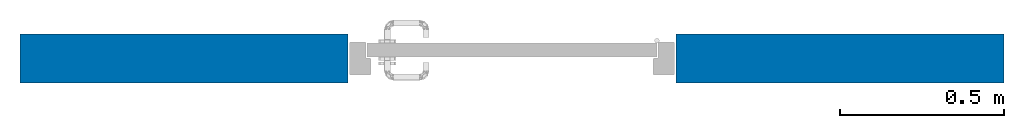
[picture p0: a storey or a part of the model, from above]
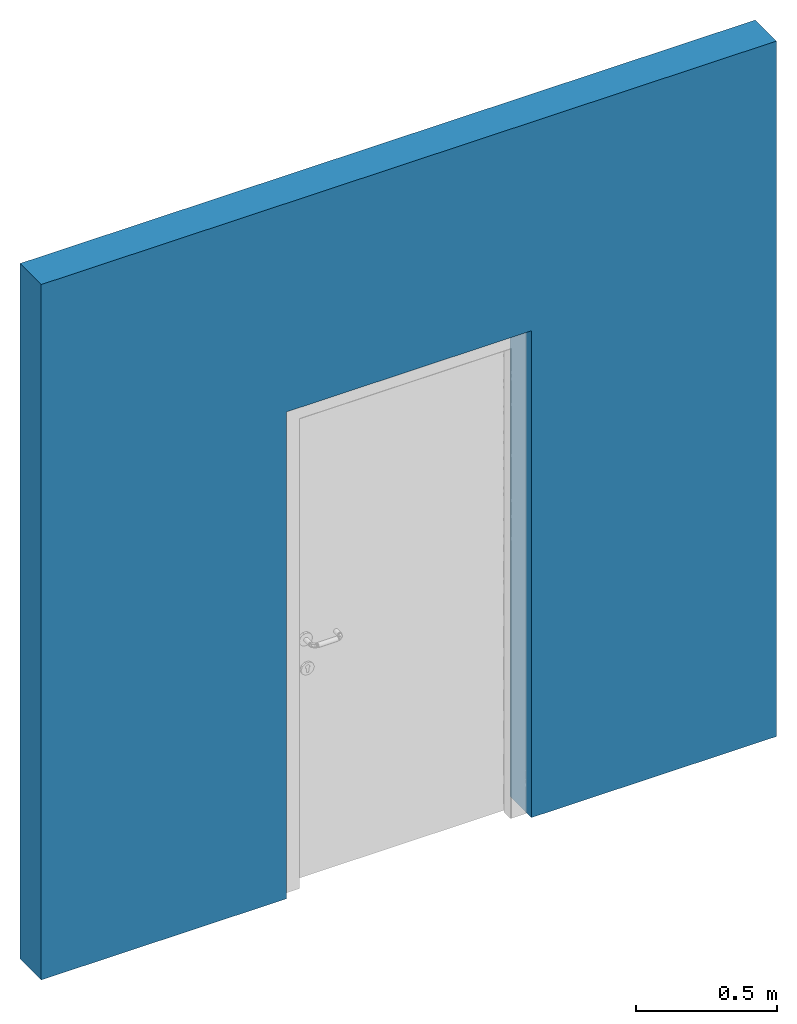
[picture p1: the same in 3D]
Properties of the parts of a building model (IFC2X3)

# File
Description: ViewDefinition [CoordinationView_V2.0]
Time: 2015-03-31T15:16:15
Written by: The EXPRESS Data Manager Version 5.01.0100.02.64mod : 6 Jun 2012
Made in: 20130709_2115(x64) - Exporter 3.12.0.0 - Alternate UI 2.12.0.0
Comment: STEP Physical File produced by: The EXPRESS Data Manager Version 5.01.0100.02.64mod : 6 Jun 2012 * Module: EDMstepFileFactory/EDMstandAlone * Creation date: Tue Mar 31 15:16:15 2015 * Host: NCL-TA29 * Database: C:\Users\Vickersc\AppData\Local\Temp\{95549542-646E-4CD0-B614-C0AC66229B2C}\ifc * Database version: 5507 * Database creation date: Tue Mar 31 15:16:13 2015 * Schema: IFC2X3 * Model: DataRepository.ifc * Model creation date: Tue Mar 31 15:16:14 2015 * Header model: DataRepository.ifc_HeaderModel * Header model creation date: Tue Mar 31 15:16:14 2015 * EDMuser: sdai-user * EDMgroup: sdai-group * License ID and type: 5605 : Permanent license. Expiry date: * EDMstepFileFactory options: 020000

# IfcProject
LongName: X:\NBL\Manufacturer\A\Assa Abloy 0060A_8204\WIP\Xbim\Batch3\IFC\NBS_AssaAbloyLtd_DrsetSym_AASDMetalThermoInsulatingUValueDoor_Single.ifc

# IfcSite, Default
RefLatitude: 42, 24, 53, 508911; RefLongitude: -71, -15, -29, -58837; RefElevation: 0 mm

# IfcBuildingStorey, Level 1
LongName: Level 1; Elevation: 0 mm

# IfcDoor: 1000x2100mm, NBS_AssaAbloyLtd_DrsetSym_AASDMetalThermoInsulatingUValueDoor_Single:1000x2100mm:1524841
In: Level 1
Type - ParameterTakesPrecedence: no; Sizeable: no; Material: NBS_Concept
Type - Pset_DoorCommon - AcousticRating: Unrated; FireExit: no; FireRating: Unrated; GlazingAreaFraction: 0; HandicapAccessible: yes; HasDrive: no; Infiltration: 0 m3/s; IsExternal: no; Reference: n/a; SecurityRating: Unrated; SelfClosing: yes; SmokeStop: no; ThermalTransmittance: 0 kg/K/s3
Type - COBie - AccessibilityPerformance: n/a; CodePerformance: n/a; Constituents: n/a; Features: n/a; Finish: n/a; Grade: n/a; Manufacturer: sales@assaabloy.co.uk; Material: n/a; ModelReference: AASD ThermoInsulating UValue Door; NominalHeight: 2100 mm; NominalLength: 0 mm; NominalWidth: 1000 mm; ReplacementCost: n/a; Shape: Rectangle; Size: 1000 x 2100 mm; SustainabilityPerformance: n/a; WarrantyDescription: n/a; WarrantyDurationParts: n/a; WarrantyGuarantorParts: n/a; AssetType: Fixed; Category: n/a; DurationUnit: year; Name: DoorsetSystem_AASDMetalThermoInsulatingUValueDoor_Single-1000x2100mm_AssaAbloyLtd; WarrantyDurationUnit: year; ExpectedLife: n/a; Description: Single metal thermo insulating U-value door; Color: n/a; ModelNumber: n/a; WarrantyDurationLabor: n/a; WarrantyGuarantorLabor: n/a
Type - NBS_General - Revision: n/a; NBSOfficeMasterTag: n/a; Author: NBS; BIMObjectName: NBS_AssaAbloyLtd_DoorsetSystem_AASDMetalThermoInsulatingUValueDoor_Single-1000x2100mm; ManufacturerName: Assa Abloy Ltd; ManufacturerURL: www.assaabloy.co.uk; NBSCertification: www.nationalbimlibrary.com/assa-abloy/single-metal-thermo-insulating-u-value-door; NBSDescription: Doorset system; NBSNote: 25-90-20/120; NBSReference: 25-50-20/120; NBSTypeID: n/a; Uniclass2: 25-30-20/120; Version: 1; ProductInformation: www.assaabloy.co.uk/en/local/uk/About-ASSA-ABLOY/UK-organisation/Security-Doors/Products1/Powershield-Doors/
Type - NBS_Data - AcousticRatingOptions: Unrated, 28 dB, 35 dB, 37 dB, 40 dB, 43 dB, 45 dB; AirTransferGrille: no; AirTransferGrilleSize: n/a; AlternativeDoorsetGlazing: n/a; AntiFingerTrapRequirement: no; AutomaticHardware: n/a; BreakoutFacility: no; CloserOptions: Push Side (AAUK ODC002), Pull Side (AAUK ODC002), None; Configuration: Single leaf, single action; DoorSeal: no; DoorsetFasteners: AASD Bespoke frame adjusters with specialised screw fixings for masonry, timber or metal; DoorsetType: Metal; DoorstopOptions: Floor mounted door stop, Wall mounted door stop; EmergencyPanicOperation: False; FireRatingOptions: Unrated, 30 minutes, 60 minutes, 120 minutes, 240 minutes; FrameFinish: n/a; FrameFinishlOptions: Epoxy powder primed, Polyester powder coated, Satin polish 180-240 grit (stainless steel only), Patterned finish (stainless steel only), Laminates; FrameMaterial: n/a; FrameMaterialOptions: Steel Galvatite ZF ‘Galvanneal’, Stainless Steel Grade 304, Stainless Steel Grade 347; FrameProfileOptions: Double Rebate, Single Rebate, Split Frame; FrameRevealFiller: n/a; FrameSeal: no; FrameWidthOptions: Available from minimum of 100 mm (Single Rebate), 146 mm (Double Rebate) and 80 mm (Split Frame); GlassType: n/a; Hanging: n/a; HardwareSetOptions: Hardware Set 1 (DT-HW-S1), Hardware Set 2 (DT-HW-P1); LeafFacingOptions: Epoxy powder primed, Polyester powder coated, Satin polish 180-240 grit (stainless steel only), Patterned finish (stainless steel only), Laminates; LeafMaterialOptions: Steel Galvatite ZF ‘Galvanneal’, Stainless Steel Grade 304, Stainless Steel Grade 316; LeafSwingOptions: Inward opening, Outward opening; LockingOptions: AAUK ECT001, AAUK EPCE001, AAUK MSL001, AAUK SMPB001; MaximumStructuralOpening: 1400 x 3000 mm; MinimumStructuralOpening: 500 x 1000 mm; Operating: n/a; OperationOptions: No operation, AAUK LH003; OverPanels: n/a; PlatesAndStops: n/a; Securing: n/a; SecurityRatingOptions: n/a; SidePanels: n/a; SignageFireOptions: AAUK FDKS001, AAUK FDKL001, None; SuitableLocation: n/a; SystemAccessories: n/a; ThresholdBase: n/a; ThresholdRequired: no; ThresholdStripping: no; Trim: n/a; VisionPanelConfiguration: n/a; VisionPanelOptions: n/a
OverallHeight: 2100 mm; OverallWidth: 1000 mm
COBie - AssetIdentifier: n/a; BarCode: n/a; InstallationDate: 1900-12-31T23:59:59; SerialNumber: n/a; TagNumber: n/a; WarrantyStartDate: n/a
NBS_Data - ComponentNumber: n/a; DoorNumber: n/a; ElectronicLock: no; FloorFinish: n/a; Handing: n/a; HardwareSet: DT-HW-S1; HeadDetail: n/a; HoldOpen: no; JambDetail: n/a; KeySuiting: n/a; LeafEdgings: n/a; LeafFacing: n/a; LeafSwing: Outward opening; OpeningMechanism: no; SignageFire: n/a; SignageSecurity: n/a; SignageWayfinding: n/a

# IfcWallStandardCase: Basic Wall:NBS_Int_Concept, Basic Wall:NBS_Int_Concept:2301
In: Level 1
Type - PredefinedType: STANDARD; Material: nbl_Concept 150 mm
